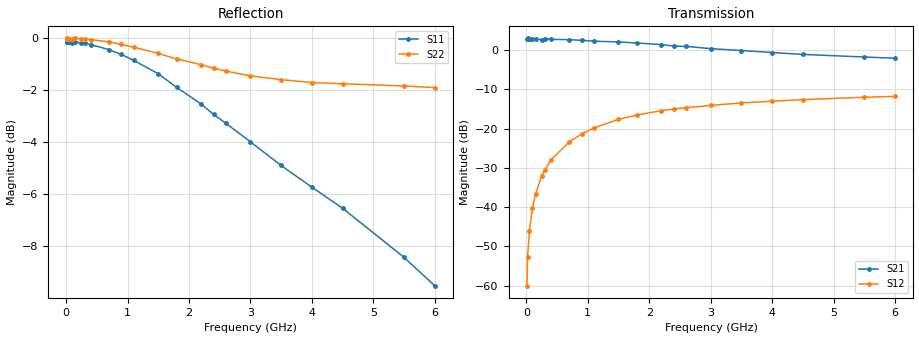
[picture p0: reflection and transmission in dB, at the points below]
! SIEMENS Discrete & RF Semiconductors
! BFY180
! Si NPN RF Bipolar Junction Transistor in MICRO-X
! VCE = 2 V  IC = 0.4 mA
! Common Emitter S-Parameters:  May  1997
# GHz  S  MA  R  50
!  f  S11  S21  S12  S22
! GHz  MAG  ANG  MAG  ANG  MAG  ANG  MAG  ANG
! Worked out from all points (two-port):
!   36 points, 10 MHz to 6 GHz, reference 50 ohm
!   highest |S21| = 2.97 dB at 20 MHz (marker M1); lowest = -2.1 dB at 6 GHz (marker M2)
!   |S21| within 3 dB of the highest: start of sweep to 3.396 GHz
!   lowest |S11| = -9.5 dB at 6 GHz (marker M3), VSWR 2.01, Z = 28.3 - j15.6 ohm
!   |S11| at or under -10 dB: nowhere
!   |S22| runs from -1.9 to 0.0 dB; largest |S21 - S12| = 1.4
!   S11 on the Smith chart (normalised r, x): 10 MHz: open; 700 MHz: 0.69, -5.10; 1.5 GHz: 0.52, -2.32; 2.4 GHz: 0.51, -1.36; 4 GHz: 0.52, -0.73; 6 GHz: 0.57, -0.31
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0.01  0.983 -0.2  1.364 179.9  0.001 93.8  0.9981 -0.2
0.02  0.9855 -0.6  1.408 179.1  0.0023 90.8  0.9999 -0.5
0.05  0.9849 -1.5  1.379 178.1  0.0049 84.6  0.999 -1.1
0.1  0.9815 -2.9  1.374 176.2  0.0098 88.4  0.9972 -2.2
0.15  0.9845 -4.7  1.384 174.2  0.0146 86.1  0.9997 -3.3
0.25  0.979 -7.9  1.359 170.1  0.0251 84.3  0.9982 -5.6
0.3  0.9799 -9.4  1.384 167.8  0.0297 83.2  0.9956 -6.6
0.4  0.9726 -12.4  1.37 163.8  0.0398 80.4  0.9947 -8.8
0.7  0.9511 -21.8  1.354 152.0  0.068 72.5  0.9845 -15.4
0.9  0.9313 -27.6  1.331 144.1  0.0851 67.5  0.9733 -19.7
1.1  0.907 -33.4  1.296 136.9  0.1018 63.0  0.9616 -23.8
1.5  0.8551 -44.9  1.268 122.4  0.1311 54.1  0.9354 -31.8
1.8  0.8049 -53.1  1.229 111.6  0.1488 48.4  0.9127 -37.2
2.2  0.7476 -63.0  1.173 98.1  0.1696 40.9  0.8899 -44.2
2.4  0.7141 -67.8  1.123 92.0  0.1773 37.8  0.8761 -47.4
2.6  0.6868 -72.2  1.113 86.0  0.1847 34.9  0.865 -50.4
3  0.6327 -80.2  1.043 75.2  0.1972 29.1  0.8469 -56.3
3.5  0.5697 -88.8  0.985 62.2  0.2121 23.3  0.8329 -63.1
4  0.5176 -97.7  0.93 50.7  0.2232 17.6  0.8225 -69.8
4.5  0.4715 -105.4  0.88 40.4  0.2337 12.4  0.8178 -76.7
5.5  0.3794 -122.7  0.815 21.0  0.2507 2.7  0.8101 -90.7
6  0.3347 -132.9  0.787 12.5  0.2571 -2.5  0.8042 -97.8
